VERSION 5.7 ;
  NOWIREEXTENSIONATPIN ON ;
  DIVIDERCHAR "/" ;
  BUSBITCHARS "[]" ;
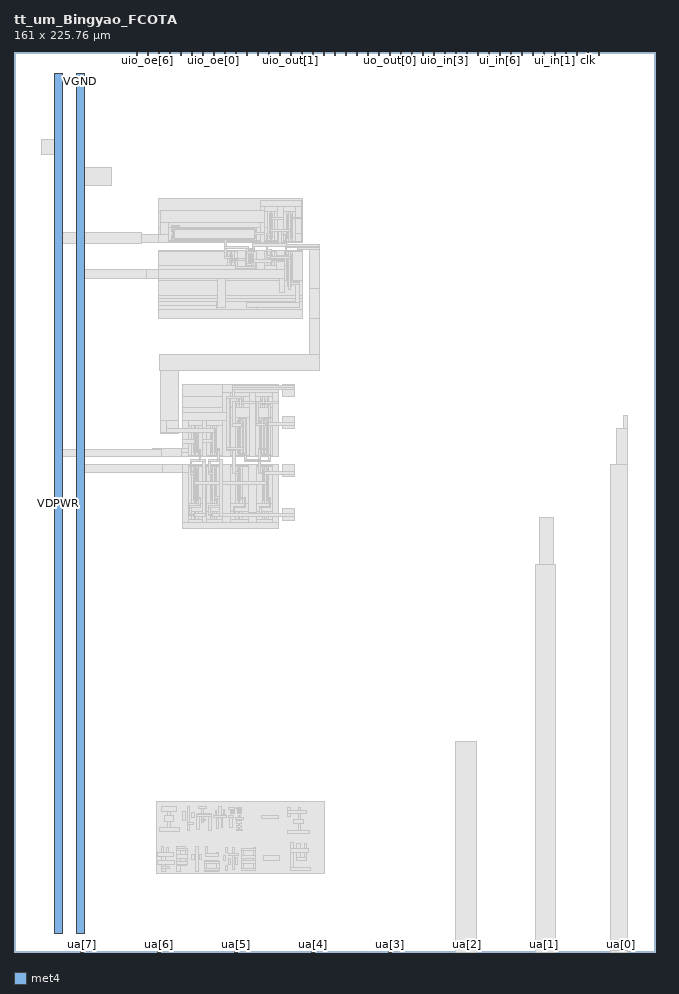
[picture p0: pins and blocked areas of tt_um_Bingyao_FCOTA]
MACRO tt_um_Bingyao_FCOTA
  CLASS BLOCK ;
  FOREIGN tt_um_Bingyao_FCOTA ;
  ORIGIN 0.000 0.000 ;
  SIZE 161.000 BY 225.760 ;
  PIN clk
    DIRECTION INPUT ;
    USE SIGNAL ;
    PORT
      LAYER met4 ;
        RECT 143.830 224.760 144.130 225.760 ;
    END
  END clk
  PIN ena
    DIRECTION INPUT ;
    USE SIGNAL ;
    PORT
      LAYER met4 ;
        RECT 146.590 224.760 146.890 225.760 ;
    END
  END ena
  PIN rst_n
    DIRECTION INPUT ;
    USE SIGNAL ;
    PORT
      LAYER met4 ;
        RECT 141.070 224.760 141.370 225.760 ;
    END
  END rst_n
  PIN ua[0]
    DIRECTION INOUT ;
    USE SIGNAL ;
    PORT
      LAYER met4 ;
        RECT 151.810 0.320 152.710 1.320 ;
    END
  END ua[0]
  PIN ua[1]
    DIRECTION INOUT ;
    USE SIGNAL ;
    PORT
      LAYER met4 ;
        RECT 132.490 0.530 133.390 1.530 ;
    END
  END ua[1]
  PIN ua[2]
    DIRECTION INOUT ;
    USE SIGNAL ;
    PORT
      LAYER met4 ;
        RECT 113.170 0.530 114.070 1.530 ;
    END
  END ua[2]
  PIN ua[3]
    DIRECTION INOUT ;
    USE SIGNAL ;
    PORT
      LAYER met4 ;
        RECT 93.850 0.000 94.750 1.000 ;
    END
  END ua[3]
  PIN ua[4]
    DIRECTION INOUT ;
    USE SIGNAL ;
    PORT
      LAYER met4 ;
        RECT 74.530 0.000 75.430 1.000 ;
    END
  END ua[4]
  PIN ua[5]
    DIRECTION INOUT ;
    USE SIGNAL ;
    PORT
      LAYER met4 ;
        RECT 55.210 0.000 56.110 1.000 ;
    END
  END ua[5]
  PIN ua[6]
    DIRECTION INOUT ;
    USE SIGNAL ;
    PORT
      LAYER met4 ;
        RECT 35.890 0.000 36.790 1.000 ;
    END
  END ua[6]
  PIN ua[7]
    DIRECTION INOUT ;
    USE SIGNAL ;
    PORT
      LAYER met4 ;
        RECT 16.570 0.000 17.470 1.000 ;
    END
  END ua[7]
  PIN ui_in[0]
    DIRECTION INPUT ;
    USE SIGNAL ;
    PORT
      LAYER met4 ;
        RECT 138.310 224.760 138.610 225.760 ;
    END
  END ui_in[0]
  PIN ui_in[1]
    DIRECTION INPUT ;
    USE SIGNAL ;
    PORT
      LAYER met4 ;
        RECT 135.550 224.760 135.850 225.760 ;
    END
  END ui_in[1]
  PIN ui_in[2]
    DIRECTION INPUT ;
    USE SIGNAL ;
    PORT
      LAYER met4 ;
        RECT 132.790 224.760 133.090 225.760 ;
    END
  END ui_in[2]
  PIN ui_in[3]
    DIRECTION INPUT ;
    USE SIGNAL ;
    PORT
      LAYER met4 ;
        RECT 130.030 224.760 130.330 225.760 ;
    END
  END ui_in[3]
  PIN ui_in[4]
    DIRECTION INPUT ;
    USE SIGNAL ;
    PORT
      LAYER met4 ;
        RECT 127.270 224.760 127.570 225.760 ;
    END
  END ui_in[4]
  PIN ui_in[5]
    DIRECTION INPUT ;
    USE SIGNAL ;
    PORT
      LAYER met4 ;
        RECT 124.510 224.760 124.810 225.760 ;
    END
  END ui_in[5]
  PIN ui_in[6]
    DIRECTION INPUT ;
    USE SIGNAL ;
    PORT
      LAYER met4 ;
        RECT 121.750 224.760 122.050 225.760 ;
    END
  END ui_in[6]
  PIN ui_in[7]
    DIRECTION INPUT ;
    USE SIGNAL ;
    PORT
      LAYER met4 ;
        RECT 118.990 224.760 119.290 225.760 ;
    END
  END ui_in[7]
  PIN uio_in[0]
    DIRECTION INPUT ;
    USE SIGNAL ;
    PORT
      LAYER met4 ;
        RECT 116.230 224.760 116.530 225.760 ;
    END
  END uio_in[0]
  PIN uio_in[1]
    DIRECTION INPUT ;
    USE SIGNAL ;
    PORT
      LAYER met4 ;
        RECT 113.470 224.760 113.770 225.760 ;
    END
  END uio_in[1]
  PIN uio_in[2]
    DIRECTION INPUT ;
    USE SIGNAL ;
    PORT
      LAYER met4 ;
        RECT 110.710 224.760 111.010 225.760 ;
    END
  END uio_in[2]
  PIN uio_in[3]
    DIRECTION INPUT ;
    USE SIGNAL ;
    PORT
      LAYER met4 ;
        RECT 107.950 224.760 108.250 225.760 ;
    END
  END uio_in[3]
  PIN uio_in[4]
    DIRECTION INPUT ;
    USE SIGNAL ;
    PORT
      LAYER met4 ;
        RECT 105.190 224.760 105.490 225.760 ;
    END
  END uio_in[4]
  PIN uio_in[5]
    DIRECTION INPUT ;
    USE SIGNAL ;
    PORT
      LAYER met4 ;
        RECT 102.430 224.760 102.730 225.760 ;
    END
  END uio_in[5]
  PIN uio_in[6]
    DIRECTION INPUT ;
    USE SIGNAL ;
    PORT
      LAYER met4 ;
        RECT 99.670 224.760 99.970 225.760 ;
    END
  END uio_in[6]
  PIN uio_in[7]
    DIRECTION INPUT ;
    USE SIGNAL ;
    PORT
      LAYER met4 ;
        RECT 96.910 224.760 97.210 225.760 ;
    END
  END uio_in[7]
  PIN uio_oe[0]
    DIRECTION OUTPUT ;
    USE SIGNAL ;
    PORT
      LAYER met4 ;
        RECT 49.990 224.760 50.290 225.760 ;
    END
  END uio_oe[0]
  PIN uio_oe[1]
    DIRECTION OUTPUT ;
    USE SIGNAL ;
    PORT
      LAYER met4 ;
        RECT 47.230 224.760 47.530 225.760 ;
    END
  END uio_oe[1]
  PIN uio_oe[2]
    DIRECTION OUTPUT ;
    USE SIGNAL ;
    PORT
      LAYER met4 ;
        RECT 44.470 224.760 44.770 225.760 ;
    END
  END uio_oe[2]
  PIN uio_oe[3]
    DIRECTION OUTPUT ;
    USE SIGNAL ;
    PORT
      LAYER met4 ;
        RECT 41.710 224.760 42.010 225.760 ;
    END
  END uio_oe[3]
  PIN uio_oe[4]
    DIRECTION OUTPUT ;
    USE SIGNAL ;
    PORT
      LAYER met4 ;
        RECT 38.950 224.760 39.250 225.760 ;
    END
  END uio_oe[4]
  PIN uio_oe[5]
    DIRECTION OUTPUT ;
    USE SIGNAL ;
    PORT
      LAYER met4 ;
        RECT 36.190 224.760 36.490 225.760 ;
    END
  END uio_oe[5]
  PIN uio_oe[6]
    DIRECTION OUTPUT ;
    USE SIGNAL ;
    PORT
      LAYER met4 ;
        RECT 33.430 224.760 33.730 225.760 ;
    END
  END uio_oe[6]
  PIN uio_oe[7]
    DIRECTION OUTPUT ;
    USE SIGNAL ;
    PORT
      LAYER met4 ;
        RECT 30.670 224.760 30.970 225.760 ;
    END
  END uio_oe[7]
  PIN uio_out[0]
    DIRECTION OUTPUT ;
    USE SIGNAL ;
    PORT
      LAYER met4 ;
        RECT 72.070 224.760 72.370 225.760 ;
    END
  END uio_out[0]
  PIN uio_out[1]
    DIRECTION OUTPUT ;
    USE SIGNAL ;
    PORT
      LAYER met4 ;
        RECT 69.310 224.760 69.610 225.760 ;
    END
  END uio_out[1]
  PIN uio_out[2]
    DIRECTION OUTPUT ;
    USE SIGNAL ;
    PORT
      LAYER met4 ;
        RECT 66.550 224.760 66.850 225.760 ;
    END
  END uio_out[2]
  PIN uio_out[3]
    DIRECTION OUTPUT ;
    USE SIGNAL ;
    PORT
      LAYER met4 ;
        RECT 63.790 224.760 64.090 225.760 ;
    END
  END uio_out[3]
  PIN uio_out[4]
    DIRECTION OUTPUT ;
    USE SIGNAL ;
    PORT
      LAYER met4 ;
        RECT 61.030 224.760 61.330 225.760 ;
    END
  END uio_out[4]
  PIN uio_out[5]
    DIRECTION OUTPUT ;
    USE SIGNAL ;
    PORT
      LAYER met4 ;
        RECT 58.270 224.760 58.570 225.760 ;
    END
  END uio_out[5]
  PIN uio_out[6]
    DIRECTION OUTPUT ;
    USE SIGNAL ;
    PORT
      LAYER met4 ;
        RECT 55.510 224.760 55.810 225.760 ;
    END
  END uio_out[6]
  PIN uio_out[7]
    DIRECTION OUTPUT ;
    USE SIGNAL ;
    PORT
      LAYER met4 ;
        RECT 52.750 224.760 53.050 225.760 ;
    END
  END uio_out[7]
  PIN uo_out[0]
    DIRECTION OUTPUT ;
    USE SIGNAL ;
    PORT
      LAYER met4 ;
        RECT 94.150 224.760 94.450 225.760 ;
    END
  END uo_out[0]
  PIN uo_out[1]
    DIRECTION OUTPUT ;
    USE SIGNAL ;
    PORT
      LAYER met4 ;
        RECT 91.390 224.760 91.690 225.760 ;
    END
  END uo_out[1]
  PIN uo_out[2]
    DIRECTION OUTPUT ;
    USE SIGNAL ;
    PORT
      LAYER met4 ;
        RECT 88.630 224.760 88.930 225.760 ;
    END
  END uo_out[2]
  PIN uo_out[3]
    DIRECTION OUTPUT ;
    USE SIGNAL ;
    PORT
      LAYER met4 ;
        RECT 85.870 224.760 86.170 225.760 ;
    END
  END uo_out[3]
  PIN uo_out[4]
    DIRECTION OUTPUT ;
    USE SIGNAL ;
    PORT
      LAYER met4 ;
        RECT 83.110 224.760 83.410 225.760 ;
    END
  END uo_out[4]
  PIN uo_out[5]
    DIRECTION OUTPUT ;
    USE SIGNAL ;
    PORT
      LAYER met4 ;
        RECT 80.350 224.760 80.650 225.760 ;
    END
  END uo_out[5]
  PIN uo_out[6]
    DIRECTION OUTPUT ;
    USE SIGNAL ;
    PORT
      LAYER met4 ;
        RECT 77.590 224.760 77.890 225.760 ;
    END
  END uo_out[6]
  PIN uo_out[7]
    DIRECTION OUTPUT ;
    USE SIGNAL ;
    PORT
      LAYER met4 ;
        RECT 74.830 224.760 75.130 225.760 ;
    END
  END uo_out[7]
  PIN VDPWR
    DIRECTION INOUT ;
    USE POWER ;
    PORT
      LAYER met4 ;
        RECT 10.220 4.690 12.220 220.450 ;
    END
  END VDPWR
  PIN VGND
    DIRECTION INOUT ;
    USE GROUND ;
    PORT
      LAYER met4 ;
        RECT 15.660 4.580 17.660 220.340 ;
    END
  END VGND
  OBS
      LAYER nwell ;
        RECT 39.315 178.015 61.275 182.205 ;
        RECT 63.290 178.010 65.650 186.200 ;
        RECT 67.930 178.000 70.290 186.190 ;
      LAYER pwell ;
        RECT 53.285 171.900 55.645 176.000 ;
        RECT 58.290 171.905 60.450 176.005 ;
        RECT 63.290 171.900 65.650 176.000 ;
        RECT 67.930 165.900 70.290 176.000 ;
        RECT 50.160 160.740 61.280 163.810 ;
      LAYER nwell ;
        RECT 55.580 136.235 57.940 139.625 ;
        RECT 61.475 136.230 63.835 139.620 ;
        RECT 44.270 124.230 46.630 132.420 ;
        RECT 48.905 124.235 51.265 132.425 ;
        RECT 55.270 124.245 58.320 134.435 ;
        RECT 61.205 124.235 64.255 134.425 ;
      LAYER pwell ;
        RECT 44.270 112.130 46.630 122.230 ;
        RECT 48.910 112.130 51.270 122.230 ;
        RECT 55.270 112.130 57.630 122.230 ;
        RECT 61.910 112.130 64.270 122.230 ;
        RECT 44.270 108.235 46.630 110.935 ;
        RECT 48.910 108.240 51.270 110.940 ;
        RECT 55.265 108.240 57.625 110.940 ;
        RECT 61.900 108.240 64.260 110.940 ;
      LAYER li1 ;
        RECT 36.285 189.020 63.670 189.030 ;
        RECT 36.285 185.830 72.280 189.020 ;
        RECT 36.285 181.810 63.670 185.830 ;
        RECT 64.270 185.340 64.670 185.510 ;
        RECT 36.285 178.365 39.665 181.810 ;
        RECT 40.295 181.345 60.295 181.515 ;
        RECT 40.065 179.090 40.235 181.130 ;
        RECT 60.355 179.090 60.525 181.130 ;
        RECT 40.295 178.705 60.295 178.875 ;
        RECT 60.925 178.365 63.660 181.810 ;
        RECT 64.040 179.085 64.210 185.125 ;
        RECT 64.730 179.085 64.900 185.125 ;
        RECT 64.270 178.700 64.670 178.870 ;
        RECT 36.285 178.360 63.660 178.365 ;
        RECT 65.290 178.360 68.300 185.830 ;
        RECT 68.910 185.330 69.310 185.500 ;
        RECT 68.680 179.075 68.850 185.115 ;
        RECT 69.370 179.075 69.540 185.115 ;
        RECT 68.910 178.690 69.310 178.860 ;
        RECT 36.285 178.350 68.300 178.360 ;
        RECT 69.940 178.350 72.280 185.830 ;
        RECT 36.285 178.195 72.280 178.350 ;
        RECT 36.285 178.010 39.660 178.195 ;
        RECT 60.930 178.190 72.280 178.195 ;
        RECT 60.930 178.000 63.660 178.190 ;
        RECT 65.290 178.180 72.280 178.190 ;
        RECT 65.290 178.010 68.300 178.180 ;
        RECT 69.940 178.030 72.280 178.180 ;
        RECT 36.280 176.030 45.820 176.040 ;
        RECT 36.280 175.820 53.620 176.030 ;
        RECT 55.270 175.825 58.640 176.000 ;
        RECT 60.060 175.825 63.640 175.990 ;
        RECT 55.270 175.820 63.640 175.825 ;
        RECT 65.290 175.820 68.300 176.040 ;
        RECT 69.940 175.820 72.280 176.010 ;
        RECT 36.280 175.655 72.280 175.820 ;
        RECT 36.280 175.650 58.640 175.655 ;
        RECT 36.280 172.280 53.635 175.650 ;
        RECT 54.265 175.140 54.665 175.310 ;
        RECT 54.035 172.930 54.205 174.970 ;
        RECT 54.725 172.930 54.895 174.970 ;
        RECT 54.265 172.590 54.665 172.760 ;
        RECT 55.270 172.280 58.640 175.650 ;
        RECT 60.060 175.650 72.280 175.655 ;
        RECT 59.205 175.145 59.535 175.315 ;
        RECT 59.040 172.935 59.210 174.975 ;
        RECT 59.530 172.935 59.700 174.975 ;
        RECT 59.205 172.595 59.535 172.765 ;
        RECT 60.060 172.280 63.640 175.650 ;
        RECT 64.270 175.140 64.670 175.310 ;
        RECT 64.040 172.930 64.210 174.970 ;
        RECT 64.730 172.930 64.900 174.970 ;
        RECT 64.270 172.590 64.670 172.760 ;
        RECT 65.290 172.280 68.300 175.650 ;
        RECT 68.910 175.140 69.310 175.310 ;
        RECT 36.280 168.400 68.300 172.280 ;
        RECT 68.680 168.400 68.850 174.970 ;
        RECT 69.370 168.400 69.540 174.970 ;
        RECT 69.940 168.400 72.280 175.650 ;
        RECT 36.270 164.560 72.310 168.400 ;
        RECT 36.250 164.010 72.310 164.560 ;
        RECT 36.250 163.960 72.330 164.010 ;
        RECT 36.240 163.270 72.330 163.960 ;
        RECT 36.240 162.240 50.700 163.270 ;
        RECT 36.250 161.230 50.700 162.240 ;
        RECT 50.990 161.570 53.150 162.980 ;
        RECT 58.290 161.570 60.450 162.980 ;
        RECT 60.820 161.230 72.330 163.270 ;
        RECT 36.250 158.870 72.340 161.230 ;
        RECT 55.530 142.260 66.270 142.280 ;
        RECT 44.350 142.250 66.270 142.260 ;
        RECT 42.250 139.230 66.270 142.250 ;
        RECT 42.250 136.600 55.930 139.230 ;
        RECT 56.560 138.765 56.960 138.935 ;
        RECT 56.330 137.310 56.500 138.550 ;
        RECT 57.020 137.310 57.190 138.550 ;
        RECT 56.560 136.925 56.960 137.095 ;
        RECT 57.570 136.600 61.840 139.230 ;
        RECT 62.455 138.760 62.855 138.930 ;
        RECT 62.225 137.305 62.395 138.545 ;
        RECT 62.915 137.305 63.085 138.545 ;
        RECT 62.455 136.920 62.855 137.090 ;
        RECT 63.485 136.600 63.655 139.230 ;
        RECT 63.870 136.600 66.250 139.230 ;
        RECT 42.250 134.080 66.250 136.600 ;
        RECT 42.250 132.075 55.620 134.080 ;
        RECT 57.950 134.075 66.250 134.080 ;
        RECT 56.250 133.575 56.650 133.745 ;
        RECT 56.940 133.575 57.340 133.745 ;
        RECT 42.250 132.070 49.270 132.075 ;
        RECT 42.250 124.580 44.640 132.070 ;
        RECT 45.250 131.560 45.650 131.730 ;
        RECT 45.020 125.305 45.190 131.345 ;
        RECT 45.710 125.305 45.880 131.345 ;
        RECT 45.250 124.920 45.650 125.090 ;
        RECT 46.220 124.585 49.270 132.070 ;
        RECT 49.885 131.565 50.285 131.735 ;
        RECT 49.655 125.310 49.825 131.350 ;
        RECT 50.345 125.310 50.515 131.350 ;
        RECT 49.885 124.925 50.285 125.095 ;
        RECT 50.915 124.595 55.620 132.075 ;
        RECT 56.020 125.320 56.190 133.360 ;
        RECT 56.710 125.320 56.880 133.360 ;
        RECT 57.400 125.320 57.570 133.360 ;
        RECT 56.250 124.935 56.650 125.105 ;
        RECT 56.940 124.935 57.340 125.105 ;
        RECT 57.950 124.595 61.570 134.075 ;
        RECT 62.185 133.565 62.585 133.735 ;
        RECT 62.875 133.565 63.275 133.735 ;
        RECT 61.955 125.310 62.125 133.350 ;
        RECT 62.645 125.310 62.815 133.350 ;
        RECT 63.335 125.310 63.505 133.350 ;
        RECT 62.185 124.925 62.585 125.095 ;
        RECT 62.875 124.925 63.275 125.095 ;
        RECT 50.915 124.585 61.570 124.595 ;
        RECT 63.870 124.585 66.250 134.075 ;
        RECT 46.220 124.580 66.250 124.585 ;
        RECT 42.250 124.425 66.250 124.580 ;
        RECT 42.250 124.415 55.600 124.425 ;
        RECT 42.250 124.410 49.270 124.415 ;
        RECT 42.250 124.250 44.640 124.410 ;
        RECT 46.220 124.220 49.270 124.410 ;
        RECT 50.920 124.240 55.600 124.415 ;
        RECT 57.950 124.415 66.250 124.425 ;
        RECT 57.950 124.270 61.570 124.415 ;
        RECT 63.870 124.270 66.250 124.415 ;
        RECT 42.230 122.050 44.610 122.240 ;
        RECT 46.270 122.050 49.280 122.230 ;
        RECT 50.920 122.050 55.620 122.230 ;
        RECT 57.270 122.050 62.270 122.230 ;
        RECT 63.910 122.050 66.260 122.250 ;
        RECT 42.230 121.880 66.260 122.050 ;
        RECT 42.230 112.500 44.620 121.880 ;
        RECT 45.250 121.370 45.650 121.540 ;
        RECT 45.020 113.160 45.190 121.200 ;
        RECT 45.710 113.160 45.880 121.200 ;
        RECT 45.250 112.820 45.650 112.990 ;
        RECT 46.270 112.500 49.280 121.880 ;
        RECT 49.890 121.370 50.290 121.540 ;
        RECT 49.660 113.160 49.830 121.200 ;
        RECT 50.350 113.160 50.520 121.200 ;
        RECT 49.890 112.820 50.290 112.990 ;
        RECT 50.920 112.500 55.620 121.880 ;
        RECT 56.250 121.370 56.650 121.540 ;
        RECT 56.020 113.160 56.190 121.200 ;
        RECT 56.710 113.160 56.880 121.200 ;
        RECT 56.250 112.820 56.650 112.990 ;
        RECT 57.270 112.500 62.270 121.880 ;
        RECT 62.890 121.370 63.290 121.540 ;
        RECT 62.660 113.160 62.830 121.200 ;
        RECT 63.350 113.160 63.520 121.200 ;
        RECT 62.890 112.820 63.290 112.990 ;
        RECT 63.910 112.500 66.260 121.880 ;
        RECT 42.230 110.580 66.260 112.500 ;
        RECT 42.230 108.590 44.620 110.580 ;
        RECT 45.250 110.075 45.650 110.245 ;
        RECT 45.020 109.265 45.190 109.905 ;
        RECT 45.710 109.265 45.880 109.905 ;
        RECT 45.250 108.925 45.650 109.095 ;
        RECT 46.270 108.590 49.280 110.580 ;
        RECT 49.890 110.080 50.290 110.250 ;
        RECT 49.660 109.270 49.830 109.910 ;
        RECT 50.350 109.270 50.520 109.910 ;
        RECT 49.890 108.930 50.290 109.100 ;
        RECT 50.920 108.590 55.620 110.580 ;
        RECT 56.245 110.080 56.645 110.250 ;
        RECT 56.015 109.270 56.185 109.910 ;
        RECT 56.705 109.270 56.875 109.910 ;
        RECT 56.245 108.930 56.645 109.100 ;
        RECT 57.270 108.590 62.270 110.580 ;
        RECT 62.880 110.080 63.280 110.250 ;
        RECT 62.650 109.270 62.820 109.910 ;
        RECT 63.340 109.270 63.510 109.910 ;
        RECT 62.880 108.930 63.280 109.100 ;
        RECT 63.910 108.590 66.260 110.580 ;
        RECT 42.230 106.230 66.270 108.590 ;
        RECT 42.230 106.220 44.610 106.230 ;
        RECT 35.670 19.810 78.000 37.770 ;
      LAYER met1 ;
        RECT 61.740 186.950 72.050 188.600 ;
        RECT 61.740 185.950 62.820 186.950 ;
        RECT 36.830 182.960 62.820 185.950 ;
        RECT 64.270 185.430 64.670 185.830 ;
        RECT 64.290 185.310 64.650 185.430 ;
        RECT 36.830 180.010 38.640 182.960 ;
        RECT 39.470 182.040 41.610 182.290 ;
        RECT 39.470 180.910 39.670 182.040 ;
        RECT 41.320 181.545 41.600 182.040 ;
        RECT 40.315 181.315 60.275 181.545 ;
        RECT 40.035 180.910 40.265 181.110 ;
        RECT 39.470 180.700 40.265 180.910 ;
        RECT 34.240 178.010 38.640 180.010 ;
        RECT 40.035 179.700 40.265 180.700 ;
        RECT 39.420 179.450 40.265 179.700 ;
        RECT 39.420 178.280 39.600 179.450 ;
        RECT 40.035 179.110 40.265 179.450 ;
        RECT 60.325 180.390 60.555 181.110 ;
        RECT 61.740 180.390 62.820 182.960 ;
        RECT 60.325 179.870 62.820 180.390 ;
        RECT 64.010 180.160 64.240 185.105 ;
        RECT 60.325 179.110 60.555 179.870 ;
        RECT 40.315 178.675 60.275 178.905 ;
        RECT 41.560 178.280 41.760 178.675 ;
        RECT 39.420 178.060 41.760 178.280 ;
        RECT 34.240 177.990 38.280 178.010 ;
        RECT 52.810 174.550 53.230 178.675 ;
        RECT 61.740 177.980 62.820 179.870 ;
        RECT 63.280 179.740 64.240 180.160 ;
        RECT 59.920 176.510 60.410 177.640 ;
        RECT 58.430 176.250 60.410 176.510 ;
        RECT 63.280 176.310 63.570 179.740 ;
        RECT 64.010 179.105 64.240 179.740 ;
        RECT 64.700 184.310 64.930 185.105 ;
        RECT 66.070 184.310 67.640 186.950 ;
        RECT 68.910 185.430 69.310 185.830 ;
        RECT 68.930 185.300 69.290 185.430 ;
        RECT 64.700 183.860 67.640 184.310 ;
        RECT 64.700 179.105 64.930 183.860 ;
        RECT 66.060 180.060 67.640 183.860 ;
        RECT 64.290 178.760 64.650 178.900 ;
        RECT 64.270 178.360 64.670 178.760 ;
        RECT 66.070 178.010 67.640 180.060 ;
        RECT 68.650 180.020 68.880 185.095 ;
        RECT 67.960 179.730 68.880 180.020 ;
        RECT 68.040 177.630 68.260 179.730 ;
        RECT 68.650 179.095 68.880 179.730 ;
        RECT 69.340 184.350 69.570 185.095 ;
        RECT 70.710 184.350 72.050 186.950 ;
        RECT 69.340 183.900 72.050 184.350 ;
        RECT 69.340 179.095 69.570 183.900 ;
        RECT 70.700 180.140 72.050 183.900 ;
        RECT 68.930 178.750 69.290 178.890 ;
        RECT 68.910 178.350 69.310 178.750 ;
        RECT 70.710 178.130 72.050 180.140 ;
        RECT 67.620 177.410 68.270 177.630 ;
        RECT 74.140 177.410 76.550 177.430 ;
        RECT 67.620 177.020 76.550 177.410 ;
        RECT 68.040 176.620 76.550 177.020 ;
        RECT 54.260 175.250 54.660 175.650 ;
        RECT 54.285 175.110 54.645 175.250 ;
        RECT 54.005 174.550 54.235 174.950 ;
        RECT 52.810 174.070 54.235 174.550 ;
        RECT 54.005 172.950 54.235 174.070 ;
        RECT 54.695 173.920 54.925 174.950 ;
        RECT 55.980 173.920 57.960 176.000 ;
        RECT 58.430 174.600 58.720 176.250 ;
        RECT 59.920 176.240 60.410 176.250 ;
        RECT 59.150 175.260 59.550 175.660 ;
        RECT 59.225 175.115 59.515 175.260 ;
        RECT 59.010 174.600 59.240 174.955 ;
        RECT 58.430 174.350 59.240 174.600 ;
        RECT 54.695 173.440 57.960 173.920 ;
        RECT 54.695 172.950 54.925 173.440 ;
        RECT 54.285 172.680 54.645 172.790 ;
        RECT 54.280 172.280 54.680 172.680 ;
        RECT 34.180 171.240 38.960 171.250 ;
        RECT 55.980 171.240 57.960 173.440 ;
        RECT 59.010 172.955 59.240 174.350 ;
        RECT 59.500 173.800 59.730 174.955 ;
        RECT 59.500 173.460 60.540 173.800 ;
        RECT 59.500 172.955 59.730 173.460 ;
        RECT 60.090 173.210 60.540 173.460 ;
        RECT 59.225 172.680 59.515 172.795 ;
        RECT 59.170 172.280 59.570 172.680 ;
        RECT 60.860 171.240 62.840 176.000 ;
        RECT 63.270 175.810 63.780 176.310 ;
        RECT 63.280 174.640 63.570 175.810 ;
        RECT 64.270 175.250 64.670 175.650 ;
        RECT 64.290 175.110 64.650 175.250 ;
        RECT 64.010 174.640 64.240 174.950 ;
        RECT 63.280 174.220 64.240 174.640 ;
        RECT 63.280 174.210 63.570 174.220 ;
        RECT 64.010 172.950 64.240 174.220 ;
        RECT 64.700 173.820 64.930 174.950 ;
        RECT 65.850 174.820 67.830 176.050 ;
        RECT 65.830 173.820 67.830 174.820 ;
        RECT 68.040 174.460 68.260 176.620 ;
        RECT 71.010 176.210 76.550 176.620 ;
        RECT 68.920 175.250 69.320 175.650 ;
        RECT 68.930 175.110 69.290 175.250 ;
        RECT 68.650 174.460 68.880 174.950 ;
        RECT 68.040 174.180 68.880 174.460 ;
        RECT 64.700 173.410 67.830 173.820 ;
        RECT 64.700 172.950 64.930 173.410 ;
        RECT 65.830 173.090 67.830 173.410 ;
        RECT 64.290 172.680 64.650 172.790 ;
        RECT 64.270 172.280 64.670 172.680 ;
        RECT 65.850 171.240 67.830 173.090 ;
        RECT 34.180 168.950 67.830 171.240 ;
        RECT 34.180 168.930 38.960 168.950 ;
        RECT 46.090 168.940 48.700 168.950 ;
        RECT 46.550 168.920 48.230 168.940 ;
        RECT 50.970 161.580 53.150 168.950 ;
        RECT 66.640 165.510 67.830 168.950 ;
        RECT 68.650 166.950 68.880 174.180 ;
        RECT 69.340 168.060 69.570 174.950 ;
        RECT 70.180 168.060 71.640 168.110 ;
        RECT 69.340 167.410 71.640 168.060 ;
        RECT 69.340 166.950 69.570 167.410 ;
        RECT 68.930 166.650 69.290 166.790 ;
        RECT 68.920 166.250 69.320 166.650 ;
        RECT 70.550 162.990 71.640 167.410 ;
        RECT 74.140 166.310 76.550 176.210 ;
        RECT 58.290 161.590 71.640 162.990 ;
        RECT 58.290 161.570 71.600 161.590 ;
        RECT 74.130 158.850 76.550 166.310 ;
        RECT 36.700 149.840 41.210 149.950 ;
        RECT 74.130 149.840 76.540 158.850 ;
        RECT 36.610 145.930 76.550 149.840 ;
        RECT 36.700 133.240 41.210 145.930 ;
        RECT 64.830 142.290 66.270 142.310 ;
        RECT 52.250 140.230 66.270 142.290 ;
        RECT 42.250 135.240 43.760 135.250 ;
        RECT 52.250 135.240 54.280 140.230 ;
        RECT 56.560 138.870 56.960 139.230 ;
        RECT 56.580 138.735 56.940 138.870 ;
        RECT 56.300 138.140 56.530 138.530 ;
        RECT 55.110 137.680 56.530 138.140 ;
        RECT 56.300 137.330 56.530 137.680 ;
        RECT 56.990 138.180 57.220 138.530 ;
        RECT 59.090 138.180 60.530 140.230 ;
        RECT 62.450 138.870 62.850 139.230 ;
        RECT 62.475 138.730 62.835 138.870 ;
        RECT 56.990 137.640 60.530 138.180 ;
        RECT 62.195 138.000 62.425 138.525 ;
        RECT 56.990 137.330 57.220 137.640 ;
        RECT 56.580 136.960 56.940 137.125 ;
        RECT 56.560 136.600 56.960 136.960 ;
        RECT 42.250 133.240 54.280 135.240 ;
        RECT 56.250 133.680 57.340 134.080 ;
        RECT 56.270 133.545 56.630 133.680 ;
        RECT 56.960 133.545 57.320 133.680 ;
        RECT 36.700 130.240 41.260 133.240 ;
        RECT 42.250 133.230 54.250 133.240 ;
        RECT 42.250 130.970 43.760 133.230 ;
        RECT 45.250 131.660 45.650 132.070 ;
        RECT 45.270 131.530 45.630 131.660 ;
        RECT 36.700 130.100 41.210 130.240 ;
        RECT 42.250 128.650 43.770 130.970 ;
        RECT 44.990 128.650 45.220 131.325 ;
        RECT 42.250 127.650 45.220 128.650 ;
        RECT 42.250 126.240 43.770 127.650 ;
        RECT 40.260 125.220 43.770 126.240 ;
        RECT 44.990 125.325 45.220 127.650 ;
        RECT 45.680 126.140 45.910 131.325 ;
        RECT 47.260 128.680 48.270 133.230 ;
        RECT 49.890 131.670 50.290 132.080 ;
        RECT 49.905 131.535 50.265 131.670 ;
        RECT 49.625 128.680 49.855 131.330 ;
        RECT 47.260 127.720 49.855 128.680 ;
        RECT 45.680 125.740 46.820 126.140 ;
        RECT 45.680 125.325 45.910 125.740 ;
        RECT 40.260 124.250 43.760 125.220 ;
        RECT 45.270 124.990 45.630 125.120 ;
        RECT 45.250 124.580 45.650 124.990 ;
        RECT 40.260 124.240 42.420 124.250 ;
        RECT 40.270 124.235 41.270 124.240 ;
        RECT 46.420 123.490 46.820 125.740 ;
        RECT 47.260 124.230 48.270 127.720 ;
        RECT 49.625 125.330 49.855 127.720 ;
        RECT 50.315 126.170 50.545 131.330 ;
        RECT 51.120 126.170 51.520 126.190 ;
        RECT 50.315 125.770 51.520 126.170 ;
        RECT 50.315 125.330 50.545 125.770 ;
        RECT 49.905 125.000 50.265 125.125 ;
        RECT 49.890 124.590 50.290 125.000 ;
        RECT 51.120 123.650 51.520 125.770 ;
        RECT 52.210 124.260 54.250 133.230 ;
        RECT 55.990 126.480 56.220 133.340 ;
        RECT 56.680 132.440 56.910 133.340 ;
        RECT 56.540 131.950 57.070 132.440 ;
        RECT 55.920 126.080 56.260 126.480 ;
        RECT 55.990 125.340 56.220 126.080 ;
        RECT 56.680 125.340 56.910 131.950 ;
        RECT 57.370 126.460 57.600 133.340 ;
        RECT 57.300 126.060 57.640 126.460 ;
        RECT 57.370 125.340 57.600 126.060 ;
        RECT 56.270 124.990 56.630 125.135 ;
        RECT 56.960 124.990 57.320 125.135 ;
        RECT 56.250 124.590 57.340 124.990 ;
        RECT 59.090 124.230 60.530 137.640 ;
        RECT 61.010 137.540 62.425 138.000 ;
        RECT 62.195 137.325 62.425 137.540 ;
        RECT 62.885 138.210 63.115 138.525 ;
        RECT 64.830 138.210 66.270 140.230 ;
        RECT 67.260 139.240 70.270 142.240 ;
        RECT 62.885 137.670 66.270 138.210 ;
        RECT 62.885 137.325 63.115 137.670 ;
        RECT 62.475 136.960 62.835 137.120 ;
        RECT 62.450 136.600 62.850 136.960 ;
        RECT 62.180 133.680 63.270 134.080 ;
        RECT 62.205 133.535 62.565 133.680 ;
        RECT 62.895 133.535 63.255 133.680 ;
        RECT 61.925 126.340 62.155 133.330 ;
        RECT 62.615 132.490 62.845 133.330 ;
        RECT 62.470 132.010 62.980 132.490 ;
        RECT 61.860 125.940 62.200 126.340 ;
        RECT 61.925 125.330 62.155 125.940 ;
        RECT 62.615 125.330 62.845 132.010 ;
        RECT 63.305 126.310 63.535 133.330 ;
        RECT 63.240 125.910 63.580 126.310 ;
        RECT 63.305 125.330 63.535 125.910 ;
        RECT 62.205 124.990 62.565 125.125 ;
        RECT 62.895 124.990 63.255 125.125 ;
        RECT 62.180 124.590 63.270 124.990 ;
        RECT 64.830 124.280 66.270 137.670 ;
        RECT 67.270 131.230 70.270 134.230 ;
        RECT 46.420 123.420 47.000 123.490 ;
        RECT 50.780 123.470 51.520 123.650 ;
        RECT 44.230 122.980 47.000 123.420 ;
        RECT 48.870 123.020 51.530 123.470 ;
        RECT 40.260 122.240 42.360 122.250 ;
        RECT 40.260 120.230 43.670 122.240 ;
        RECT 44.230 120.600 44.620 122.980 ;
        RECT 45.250 121.470 45.650 121.880 ;
        RECT 45.270 121.340 45.630 121.470 ;
        RECT 44.990 120.600 45.220 121.180 ;
        RECT 44.230 120.320 45.220 120.600 ;
        RECT 42.220 107.810 43.670 120.230 ;
        RECT 44.240 119.870 45.220 120.320 ;
        RECT 44.990 113.180 45.220 119.870 ;
        RECT 45.680 114.130 45.910 121.180 ;
        RECT 45.680 113.690 46.840 114.130 ;
        RECT 45.680 113.180 45.910 113.690 ;
        RECT 45.270 112.910 45.630 113.020 ;
        RECT 45.260 112.500 45.660 112.910 ;
        RECT 46.400 111.940 46.840 113.690 ;
        RECT 44.070 111.490 46.850 111.940 ;
        RECT 44.070 109.810 44.510 111.490 ;
        RECT 45.250 110.180 45.650 110.580 ;
        RECT 45.270 110.045 45.630 110.180 ;
        RECT 44.990 109.810 45.220 109.885 ;
        RECT 44.070 109.620 45.220 109.810 ;
        RECT 44.080 109.370 45.220 109.620 ;
        RECT 44.990 109.285 45.220 109.370 ;
        RECT 45.680 109.780 45.910 109.885 ;
        RECT 47.240 109.780 48.280 122.240 ;
        RECT 48.870 120.560 49.260 123.020 ;
        RECT 49.900 121.470 50.300 121.880 ;
        RECT 49.910 121.340 50.270 121.470 ;
        RECT 49.630 120.560 49.860 121.180 ;
        RECT 48.870 120.300 49.860 120.560 ;
        RECT 48.890 119.830 49.860 120.300 ;
        RECT 49.630 113.180 49.860 119.830 ;
        RECT 50.320 114.180 50.550 121.180 ;
        RECT 50.320 113.740 51.490 114.180 ;
        RECT 50.320 113.180 50.550 113.740 ;
        RECT 49.910 112.910 50.270 113.020 ;
        RECT 49.890 112.500 50.290 112.910 ;
        RECT 51.050 111.930 51.490 113.740 ;
        RECT 48.710 111.480 51.490 111.930 ;
        RECT 45.680 109.340 48.280 109.780 ;
        RECT 48.730 109.810 49.170 111.480 ;
        RECT 49.890 110.200 50.290 110.580 ;
        RECT 49.910 110.050 50.270 110.200 ;
        RECT 52.260 110.040 54.280 122.230 ;
        RECT 56.250 121.470 56.650 121.880 ;
        RECT 56.270 121.340 56.630 121.470 ;
        RECT 54.760 120.430 55.450 120.500 ;
        RECT 55.990 120.430 56.220 121.180 ;
        RECT 54.760 120.040 56.220 120.430 ;
        RECT 55.990 113.180 56.220 120.040 ;
        RECT 56.680 114.070 56.910 121.180 ;
        RECT 57.720 114.070 58.080 114.080 ;
        RECT 56.680 113.720 58.080 114.070 ;
        RECT 56.680 113.180 56.910 113.720 ;
        RECT 56.270 112.910 56.630 113.020 ;
        RECT 56.250 112.500 56.650 112.910 ;
        RECT 57.720 111.730 58.080 113.720 ;
        RECT 55.030 111.420 58.080 111.730 ;
        RECT 49.630 109.810 49.860 109.890 ;
        RECT 48.730 109.370 49.860 109.810 ;
        RECT 45.680 109.285 45.910 109.340 ;
        RECT 45.270 108.990 45.630 109.125 ;
        RECT 45.250 108.590 45.650 108.990 ;
        RECT 47.240 107.810 48.280 109.340 ;
        RECT 49.630 109.290 49.860 109.370 ;
        RECT 50.320 109.780 50.550 109.890 ;
        RECT 52.250 109.780 54.280 110.040 ;
        RECT 50.320 109.360 54.280 109.780 ;
        RECT 55.040 109.710 55.400 111.420 ;
        RECT 56.250 110.170 56.650 110.580 ;
        RECT 56.265 110.050 56.625 110.170 ;
        RECT 58.880 110.130 60.900 122.230 ;
        RECT 62.890 121.470 63.290 121.880 ;
        RECT 62.910 121.340 63.270 121.470 ;
        RECT 61.270 120.370 61.830 120.490 ;
        RECT 62.630 120.370 62.860 121.180 ;
        RECT 61.270 119.980 62.860 120.370 ;
        RECT 62.630 113.180 62.860 119.980 ;
        RECT 63.320 114.040 63.550 121.180 ;
        RECT 63.990 114.040 64.350 114.050 ;
        RECT 63.320 113.700 64.360 114.040 ;
        RECT 63.320 113.180 63.550 113.700 ;
        RECT 62.910 112.910 63.270 113.020 ;
        RECT 62.890 112.500 63.290 112.910 ;
        RECT 63.990 111.820 64.350 113.700 ;
        RECT 61.660 111.540 64.350 111.820 ;
        RECT 55.985 109.710 56.215 109.890 ;
        RECT 55.030 109.420 56.215 109.710 ;
        RECT 50.320 109.290 50.550 109.360 ;
        RECT 52.250 109.240 54.280 109.360 ;
        RECT 55.985 109.290 56.215 109.420 ;
        RECT 56.675 109.760 56.905 109.890 ;
        RECT 58.870 109.760 60.900 110.130 ;
        RECT 56.675 109.440 60.900 109.760 ;
        RECT 56.675 109.290 56.905 109.440 ;
        RECT 58.870 109.250 60.900 109.440 ;
        RECT 61.670 109.700 62.030 111.540 ;
        RECT 62.880 110.180 63.280 110.590 ;
        RECT 62.900 110.050 63.260 110.180 ;
        RECT 62.620 109.700 62.850 109.890 ;
        RECT 61.670 109.410 62.850 109.700 ;
        RECT 62.620 109.290 62.850 109.410 ;
        RECT 63.310 109.750 63.540 109.890 ;
        RECT 64.750 109.750 66.260 122.260 ;
        RECT 67.250 119.220 70.260 122.240 ;
        RECT 63.310 109.450 66.260 109.750 ;
        RECT 63.310 109.290 63.540 109.450 ;
        RECT 49.910 108.970 50.270 109.130 ;
        RECT 49.890 108.590 50.290 108.970 ;
        RECT 52.260 107.810 54.280 109.240 ;
        RECT 56.265 109.000 56.625 109.130 ;
        RECT 56.250 108.590 56.650 109.000 ;
        RECT 58.880 107.810 60.900 109.250 ;
        RECT 62.900 109.000 63.260 109.130 ;
        RECT 62.880 108.590 63.280 109.000 ;
        RECT 64.750 107.810 66.260 109.450 ;
        RECT 67.260 108.240 70.280 111.240 ;
        RECT 42.220 106.240 66.260 107.810 ;
        RECT 42.220 106.230 66.250 106.240 ;
        RECT 36.960 35.240 40.760 36.540 ;
        RECT 38.390 34.190 39.310 35.240 ;
        RECT 37.680 32.850 39.970 34.190 ;
        RECT 42.310 33.050 43.080 35.130 ;
        RECT 38.390 31.270 39.310 32.850 ;
        RECT 43.630 32.500 44.070 36.580 ;
        RECT 46.350 35.900 48.280 36.550 ;
        RECT 44.640 33.790 45.360 34.930 ;
        RECT 47.030 34.650 47.640 35.900 ;
        RECT 46.090 34.470 49.530 34.650 ;
        RECT 45.850 33.880 49.530 34.470 ;
        RECT 50.460 34.360 50.740 35.460 ;
        RECT 51.420 34.360 51.950 36.400 ;
        RECT 53.690 36.330 55.170 36.360 ;
        RECT 53.690 35.830 55.360 36.330 ;
        RECT 52.580 34.540 52.860 35.620 ;
        RECT 54.900 35.540 55.360 35.830 ;
        RECT 55.790 36.050 57.080 36.340 ;
        RECT 55.790 35.820 57.120 36.050 ;
        RECT 56.600 35.540 57.120 35.820 ;
        RECT 54.400 35.190 55.360 35.540 ;
        RECT 56.000 35.200 57.120 35.540 ;
        RECT 54.900 35.000 55.360 35.190 ;
        RECT 56.600 35.030 57.120 35.200 ;
        RECT 54.410 34.690 55.360 35.000 ;
        RECT 56.120 34.750 57.120 35.030 ;
        RECT 68.730 35.560 69.300 36.200 ;
        RECT 71.260 35.560 71.900 36.270 ;
        RECT 68.730 34.810 73.370 35.560 ;
        RECT 56.120 34.690 56.860 34.750 ;
        RECT 54.410 34.650 54.950 34.690 ;
        RECT 52.390 34.360 53.030 34.540 ;
        RECT 43.630 31.880 45.100 32.500 ;
        RECT 36.410 30.260 41.610 31.270 ;
        RECT 43.630 30.480 44.070 31.880 ;
        RECT 45.850 30.630 46.460 33.880 ;
        RECT 47.030 33.240 47.640 33.880 ;
        RECT 47.030 32.870 48.000 33.240 ;
        RECT 47.030 32.410 47.640 32.870 ;
        RECT 48.880 30.590 49.490 33.880 ;
        RECT 49.930 33.730 53.400 34.360 ;
        RECT 53.730 33.740 55.170 34.290 ;
        RECT 56.280 33.910 56.810 34.320 ;
        RECT 50.810 30.980 51.250 33.730 ;
        RECT 51.970 31.300 52.410 33.730 ;
        RECT 54.180 31.200 54.730 33.740 ;
        RECT 55.610 33.270 57.450 33.760 ;
        RECT 62.020 33.450 66.300 34.200 ;
        RECT 68.730 34.090 69.300 34.810 ;
        RECT 71.260 33.270 71.900 34.810 ;
        RECT 56.370 32.880 56.630 33.270 ;
        RECT 55.870 32.300 57.070 32.880 ;
        RECT 56.370 31.830 56.630 32.300 ;
        RECT 70.190 32.130 72.720 33.270 ;
        RECT 55.870 31.250 57.070 31.830 ;
        RECT 56.370 30.740 56.630 31.250 ;
        RECT 55.720 30.360 57.340 30.740 ;
        RECT 71.260 30.530 71.900 32.130 ;
        RECT 68.730 29.630 74.220 30.530 ;
        RECT 40.860 26.340 41.780 26.370 ;
        RECT 37.030 24.990 37.570 26.340 ;
        RECT 38.310 24.990 38.850 26.270 ;
        RECT 40.860 26.020 43.110 26.340 ;
        RECT 40.860 25.370 43.520 26.020 ;
        RECT 35.880 23.920 40.120 24.990 ;
        RECT 40.860 24.460 41.780 25.370 ;
        RECT 42.960 24.460 43.520 25.370 ;
        RECT 36.990 23.060 37.880 23.920 ;
        RECT 40.860 23.490 43.520 24.460 ;
        RECT 36.040 21.990 40.280 23.060 ;
        RECT 40.860 22.740 41.780 23.490 ;
        RECT 42.960 22.740 43.520 23.490 ;
        RECT 44.515 23.205 45.155 24.435 ;
        RECT 36.990 21.450 37.880 21.990 ;
        RECT 40.860 21.860 43.520 22.740 ;
        RECT 40.860 21.770 43.300 21.860 ;
        RECT 36.990 20.900 38.900 21.450 ;
        RECT 36.990 20.110 37.880 20.900 ;
        RECT 40.860 20.150 41.780 21.770 ;
        RECT 45.460 20.210 46.170 26.440 ;
        RECT 48.160 24.770 48.640 26.500 ;
        RECT 50.880 24.770 51.310 25.080 ;
        RECT 52.940 25.010 53.440 26.260 ;
        RECT 54.740 24.770 55.350 26.130 ;
        RECT 60.000 26.040 60.670 26.110 ;
        RECT 56.960 25.370 60.670 26.040 ;
        RECT 46.450 23.240 47.090 24.470 ;
        RECT 48.150 24.050 51.400 24.770 ;
        RECT 53.880 24.270 56.340 24.770 ;
        RECT 47.840 22.850 51.280 23.000 ;
        RECT 52.640 22.850 53.140 24.100 ;
        RECT 47.730 22.710 51.280 22.850 ;
        RECT 47.730 22.320 51.430 22.710 ;
        RECT 47.730 20.960 48.320 22.320 ;
        RECT 50.740 20.960 51.430 22.320 ;
        RECT 53.760 22.020 54.270 23.570 ;
        RECT 47.730 20.530 51.430 20.960 ;
        RECT 47.810 20.500 51.430 20.530 ;
        RECT 52.950 20.510 53.450 21.760 ;
        RECT 54.740 20.610 55.350 24.270 ;
        RECT 56.970 24.160 57.470 25.370 ;
        RECT 60.000 24.160 60.670 25.370 ;
        RECT 55.650 22.070 56.160 23.620 ;
        RECT 56.970 23.490 60.670 24.160 ;
        RECT 69.340 26.060 70.160 27.390 ;
        RECT 70.940 26.060 71.900 27.100 ;
        RECT 72.830 26.060 73.470 27.240 ;
        RECT 69.340 25.030 73.930 26.060 ;
        RECT 56.970 22.920 57.470 23.490 ;
        RECT 60.000 22.920 60.670 23.490 ;
        RECT 62.560 23.070 66.660 24.100 ;
        RECT 56.970 22.250 60.670 22.920 ;
        RECT 56.970 20.990 57.470 22.250 ;
        RECT 60.000 20.990 60.670 22.250 ;
        RECT 47.810 20.280 51.250 20.500 ;
        RECT 56.970 20.420 60.670 20.990 ;
        RECT 57.070 20.370 60.670 20.420 ;
        RECT 69.340 21.320 70.160 25.030 ;
        RECT 70.940 23.710 71.900 25.030 ;
        RECT 72.830 23.710 73.470 25.030 ;
        RECT 70.940 22.860 73.470 23.710 ;
        RECT 57.070 20.320 60.350 20.370 ;
        RECT 69.340 20.320 74.370 21.320 ;
      LAYER met2 ;
        RECT 64.270 181.310 64.680 185.830 ;
        RECT 68.900 181.310 69.310 185.820 ;
        RECT 64.270 180.610 69.310 181.310 ;
        RECT 29.870 177.930 36.240 180.080 ;
        RECT 64.270 178.360 64.680 180.610 ;
        RECT 66.440 177.650 67.020 180.610 ;
        RECT 68.900 178.350 69.310 180.610 ;
        RECT 59.890 177.640 67.020 177.650 ;
        RECT 59.890 177.020 68.260 177.640 ;
        RECT 66.440 177.010 68.260 177.020 ;
        RECT 52.810 176.430 58.700 176.910 ;
        RECT 58.370 175.660 58.700 176.430 ;
        RECT 63.270 175.810 64.670 176.320 ;
        RECT 54.270 173.810 54.670 175.650 ;
        RECT 58.370 175.290 59.560 175.660 ;
        RECT 55.530 173.810 55.980 173.820 ;
        RECT 54.270 173.350 55.980 173.810 ;
        RECT 54.270 172.290 54.670 173.350 ;
        RECT 55.530 171.920 55.980 173.350 ;
        RECT 58.370 172.620 58.700 175.290 ;
        RECT 64.270 174.550 64.670 175.810 ;
        RECT 68.920 174.550 69.330 175.650 ;
        RECT 64.270 173.850 69.330 174.550 ;
        RECT 60.100 173.610 60.550 173.810 ;
        RECT 64.270 173.610 64.670 173.850 ;
        RECT 60.100 172.960 64.670 173.610 ;
        RECT 58.370 172.270 59.570 172.620 ;
        RECT 60.100 171.920 60.550 172.960 ;
        RECT 64.270 172.270 64.670 172.960 ;
        RECT 55.520 171.460 60.550 171.920 ;
        RECT 30.830 168.920 36.190 171.290 ;
        RECT 68.920 166.260 69.330 173.850 ;
        RECT 67.260 141.980 70.280 142.230 ;
        RECT 54.800 141.680 70.280 141.980 ;
        RECT 54.790 141.120 70.280 141.680 ;
        RECT 54.790 139.260 55.430 141.120 ;
        RECT 53.770 139.250 56.660 139.260 ;
        RECT 53.360 139.240 56.660 139.250 ;
        RECT 67.260 139.240 70.280 141.120 ;
        RECT 53.360 138.800 56.970 139.240 ;
        RECT 38.260 131.370 41.260 133.240 ;
        RECT 45.240 131.370 45.650 132.080 ;
        RECT 49.890 131.370 50.290 132.070 ;
        RECT 38.260 130.240 50.290 131.370 ;
        RECT 40.780 130.210 50.290 130.240 ;
        RECT 34.810 124.220 42.100 126.220 ;
        RECT 45.240 124.590 45.650 130.210 ;
        RECT 49.890 124.580 50.290 130.210 ;
        RECT 53.360 126.460 54.030 138.800 ;
        RECT 54.890 132.450 55.510 138.140 ;
        RECT 56.560 136.600 56.970 138.800 ;
        RECT 56.540 133.770 58.340 134.090 ;
        RECT 54.890 131.930 57.080 132.450 ;
        RECT 55.090 131.920 57.080 131.930 ;
        RECT 53.360 126.060 57.640 126.460 ;
        RECT 53.360 125.800 55.460 126.060 ;
        RECT 53.360 125.790 54.030 125.800 ;
        RECT 46.430 122.980 47.970 123.490 ;
        RECT 50.780 123.020 52.280 123.650 ;
        RECT 34.940 120.230 42.230 122.230 ;
        RECT 45.260 118.030 45.650 121.880 ;
        RECT 47.340 118.030 47.960 122.980 ;
        RECT 49.880 118.030 50.290 121.880 ;
        RECT 54.760 120.050 55.460 125.800 ;
        RECT 57.980 124.930 58.320 133.770 ;
        RECT 60.920 132.510 61.450 138.010 ;
        RECT 62.440 137.670 62.850 139.240 ;
        RECT 62.440 137.240 64.260 137.670 ;
        RECT 62.440 136.600 62.850 137.240 ;
        RECT 63.860 134.070 64.260 137.240 ;
        RECT 62.480 133.840 64.260 134.070 ;
        RECT 62.480 133.770 64.250 133.840 ;
        RECT 63.910 132.700 64.250 133.770 ;
        RECT 67.260 132.700 70.280 134.220 ;
        RECT 60.920 131.980 62.990 132.510 ;
        RECT 60.920 131.950 61.450 131.980 ;
        RECT 63.910 131.960 70.280 132.700 ;
        RECT 56.540 124.860 58.320 124.930 ;
        RECT 61.270 126.330 61.830 126.340 ;
        RECT 61.270 125.930 63.590 126.330 ;
        RECT 56.540 124.590 58.330 124.860 ;
        RECT 57.930 123.660 58.330 124.590 ;
        RECT 61.270 123.660 61.830 125.930 ;
        RECT 63.910 124.880 64.250 131.960 ;
        RECT 67.260 131.230 70.280 131.960 ;
        RECT 62.480 124.580 64.250 124.880 ;
        RECT 57.930 123.380 61.830 123.660 ;
        RECT 63.760 123.380 64.240 124.580 ;
        RECT 57.930 123.180 64.240 123.380 ;
        RECT 57.930 123.080 64.230 123.180 ;
        RECT 61.270 122.940 64.230 123.080 ;
        RECT 56.230 118.030 56.660 121.880 ;
        RECT 61.270 119.980 61.830 122.940 ;
        RECT 62.870 120.460 63.300 121.890 ;
        RECT 67.250 120.460 70.270 122.230 ;
        RECT 62.870 119.680 70.270 120.460 ;
        RECT 62.870 118.030 63.300 119.680 ;
        RECT 67.250 119.240 70.270 119.680 ;
        RECT 45.200 117.340 63.300 118.030 ;
        RECT 45.260 112.500 45.650 117.340 ;
        RECT 45.250 109.960 45.650 110.590 ;
        RECT 47.340 109.960 47.960 117.340 ;
        RECT 49.880 112.490 50.290 117.340 ;
        RECT 56.230 112.480 56.660 117.340 ;
        RECT 62.870 112.490 63.300 117.340 ;
        RECT 45.250 109.280 48.000 109.960 ;
        RECT 49.890 109.900 50.290 110.590 ;
        RECT 56.220 109.900 56.650 110.590 ;
        RECT 62.880 110.060 63.310 110.580 ;
        RECT 67.280 110.060 70.300 111.220 ;
        RECT 62.880 109.900 70.300 110.060 ;
        RECT 45.250 108.590 45.650 109.280 ;
        RECT 47.340 109.260 47.960 109.280 ;
        RECT 49.890 109.270 70.300 109.900 ;
        RECT 49.890 108.590 50.290 109.270 ;
        RECT 56.220 108.600 56.650 109.270 ;
        RECT 62.880 109.230 70.300 109.270 ;
        RECT 62.880 108.590 63.310 109.230 ;
        RECT 67.280 108.230 70.300 109.230 ;
      LAYER met3 ;
        RECT 10.220 177.800 32.070 180.390 ;
        RECT 15.600 168.880 33.120 171.290 ;
        RECT 10.210 124.180 37.080 126.160 ;
        RECT 15.680 120.215 37.350 122.220 ;
        RECT 51.540 109.240 52.280 123.660 ;
      LAYER met4 ;
        RECT 6.830 199.960 10.220 203.810 ;
        RECT 17.660 192.200 24.350 196.770 ;
        RECT 152.980 131.320 153.770 134.480 ;
        RECT 151.080 122.300 153.770 131.320 ;
        RECT 131.850 97.190 135.250 109.080 ;
        RECT 110.870 1.530 115.950 52.900 ;
        RECT 110.870 0.530 113.170 1.530 ;
        RECT 114.070 0.530 115.950 1.530 ;
        RECT 110.870 0.000 115.950 0.530 ;
        RECT 130.700 1.530 135.920 97.190 ;
        RECT 130.700 0.530 132.490 1.530 ;
        RECT 133.390 0.530 135.920 1.530 ;
        RECT 130.700 0.000 135.920 0.530 ;
        RECT 149.750 1.320 153.770 122.300 ;
        RECT 149.750 0.320 151.810 1.320 ;
        RECT 152.710 0.320 153.770 1.320 ;
        RECT 149.750 0.000 153.770 0.320 ;
  END
END tt_um_Bingyao_FCOTA
END LIBRARY

